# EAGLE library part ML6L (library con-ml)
HARTING

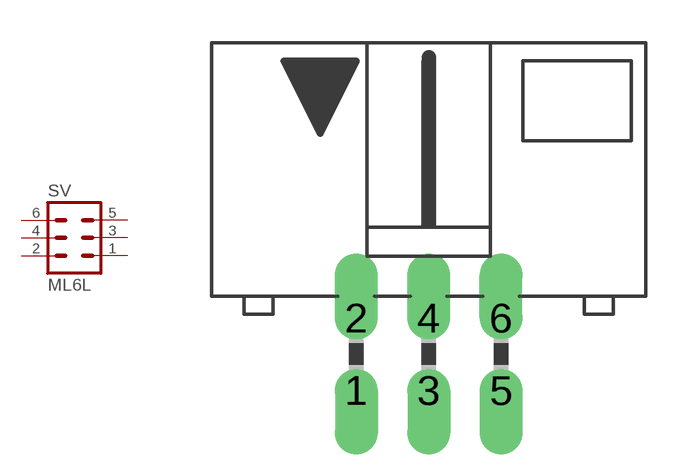
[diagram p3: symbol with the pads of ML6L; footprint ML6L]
Designator prefix SV

## ML6L (OC_FARNELL: unknown; OC_NEWARK: unknown)  [ML6L]
1  1  pas
2  2  pas
3  3  pas
4  4  pas
5  5  pas
6  6  pas

## Footprint ML6L (pad centres in mm)
HARTING
drill 0.914 pad 1.5 offset: 1 -2.54,-1.27; 2 -2.54,1.27; 3 0,-1.27; 4 0,1.27; 5 2.54,-1.27; 6 2.54,1.27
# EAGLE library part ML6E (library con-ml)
HARTING

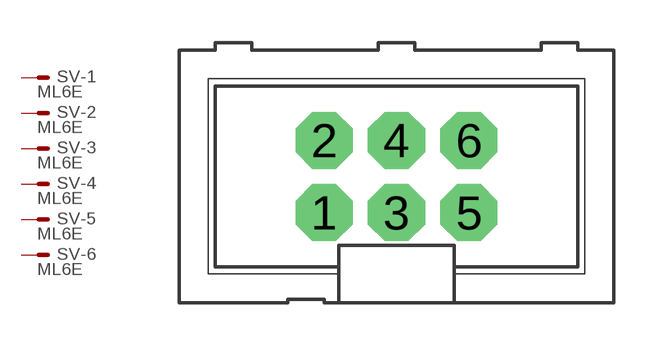
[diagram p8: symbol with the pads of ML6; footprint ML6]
Designator prefix SV; gates -1=M -2=M -3=M -4=M -5=M -6=M

## ML6E (OC_FARNELL: unknown; OC_NEWARK: unknown)  [ML6]
1  -1:S  pas
2  -2:S  pas
3  -3:S  pas
4  -4:S  pas
5  -5:S  pas
6  -6:S  pas

## Footprint ML6 (pad centres in mm)
HARTING
drill 0.914 pad 2 octagon: 1 -2.54,-1.27; 2 -2.54,1.27; 3 0,-1.27; 4 0,1.27; 5 2.54,-1.27; 6 2.54,1.27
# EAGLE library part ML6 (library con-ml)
HARTING

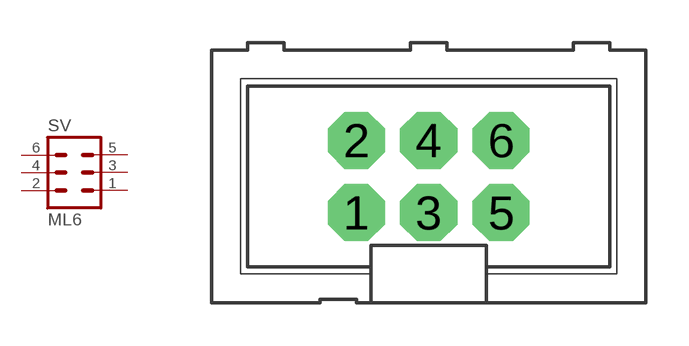
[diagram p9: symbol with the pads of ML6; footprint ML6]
Designator prefix SV

## ML6 (OC_FARNELL: unknown; OC_NEWARK: unknown)  [ML6]
1  1  pas
2  2  pas
3  3  pas
4  4  pas
5  5  pas
6  6  pas

## Footprint ML6 (pad centres in mm)
HARTING
drill 0.914 pad 2 octagon: 1 -2.54,-1.27; 2 -2.54,1.27; 3 0,-1.27; 4 0,1.27; 5 2.54,-1.27; 6 2.54,1.27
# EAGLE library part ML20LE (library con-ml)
HARTING

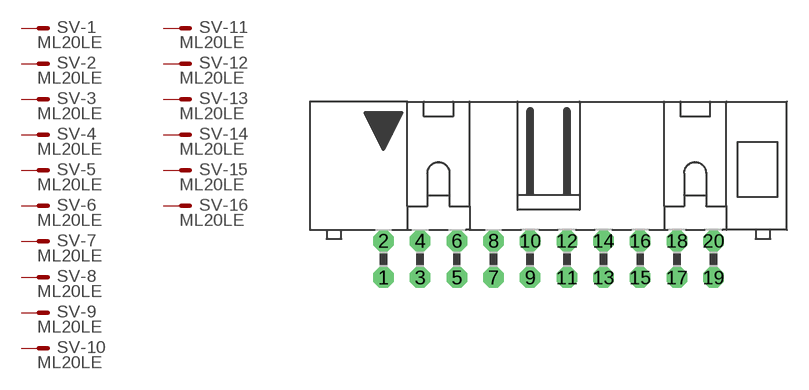
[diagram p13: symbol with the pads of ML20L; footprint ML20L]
Designator prefix SV; gates -1=M -2=M -3=M -4=M -5=M -6=M -7=M -8=M -9=M -10=M -11=M -12=M -13=M -14=M -15=M -16=M -17=M -18=M -19=M -20=M

## ML20LE (OC_FARNELL: unknown; OC_NEWARK: unknown)  [ML20L]
1  -1:S  pas
2  -2:S  pas
3  -3:S  pas
4  -4:S  pas
5  -5:S  pas
6  -6:S  pas
7  -7:S  pas
8  -8:S  pas
9  -9:S  pas
10  -10:S  pas
11  -11:S  pas
12  -12:S  pas
13  -13:S  pas
14  -14:S  pas
15  -15:S  pas
16  -16:S  pas
17  -17:S  pas
18  -18:S  pas
19  -19:S  pas
20  -20:S  pas

## Footprint ML20L (pad centres in mm)
HARTING
drill 0.914 octagon: 1 -11.43,-1.27; 2 -11.43,1.27; 3 -8.89,-1.27; 4 -8.89,1.27; 5 -6.35,-1.27; 6 -6.35,1.27; 7 -3.81,-1.27; 8 -3.81,1.27; 9 -1.27,-1.27; 10 -1.27,1.27; 11 1.27,-1.27; 12 1.27,1.27; 13 3.81,-1.27; 14 3.81,1.27; 15 6.35,-1.27; 16 6.35,1.27; 17 8.89,-1.27; 18 8.89,1.27; 19 11.43,-1.27; 20 11.43,1.27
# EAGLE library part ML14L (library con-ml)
HARTING

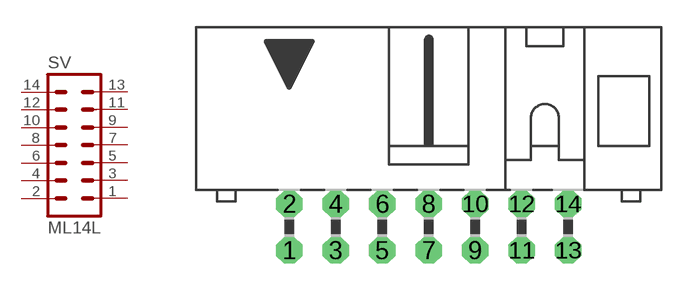
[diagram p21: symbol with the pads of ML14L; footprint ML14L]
Designator prefix SV

## ML14L (OC_FARNELL: unknown; OC_NEWARK: unknown)  [ML14L]
1  1  pas
2  2  pas
3  3  pas
4  4  pas
5  5  pas
6  6  pas
7  7  pas
8  8  pas
9  9  pas
10  10  pas
11  11  pas
12  12  pas
13  13  pas
14  14  pas

## Footprint ML14L (pad centres in mm)
HARTING
drill 0.914 octagon: 1 -7.62,-1.27; 2 -7.62,1.27; 3 -5.08,-1.27; 4 -5.08,1.27; 5 -2.54,-1.27; 6 -2.54,1.27; 7 0,-1.27; 8 0,1.27; 9 2.54,-1.27; 10 2.54,1.27; 11 5.08,-1.27; 12 5.08,1.27; 13 7.62,-1.27; 14 7.62,1.27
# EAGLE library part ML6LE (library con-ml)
HARTING

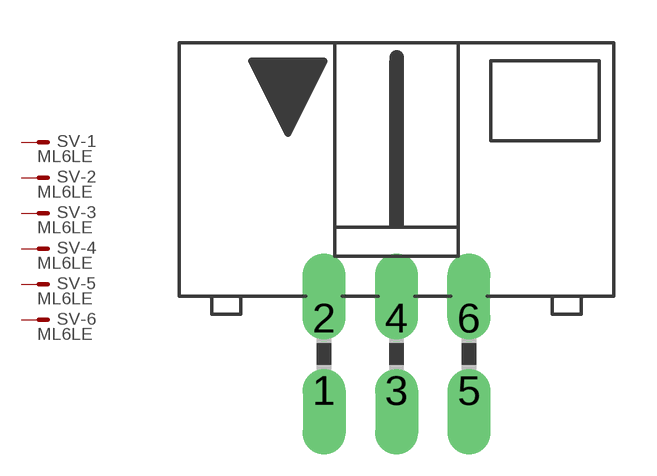
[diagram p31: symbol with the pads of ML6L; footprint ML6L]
Designator prefix SV; gates -1=M -2=M -3=M -4=M -5=M -6=M

## ML6LE (OC_FARNELL: unknown; OC_NEWARK: unknown)  [ML6L]
1  -1:S  pas
2  -2:S  pas
3  -3:S  pas
4  -4:S  pas
5  -5:S  pas
6  -6:S  pas

## Footprint ML6L (pad centres in mm)
HARTING
drill 0.914 pad 1.5 offset: 1 -2.54,-1.27; 2 -2.54,1.27; 3 0,-1.27; 4 0,1.27; 5 2.54,-1.27; 6 2.54,1.27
